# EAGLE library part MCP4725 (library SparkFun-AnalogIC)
Microchip 12-bit I2C DAC, SOT23-6

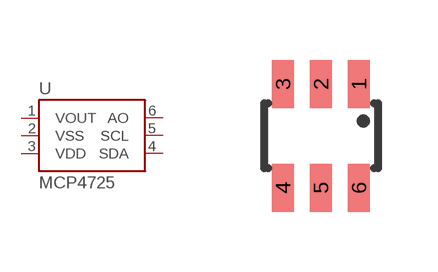
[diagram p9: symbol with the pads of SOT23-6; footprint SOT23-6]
Designator prefix U

## MCP4725SOT-23 (PROD_ID: IC-08886; VALUE: MCP4725)  [SOT23-6]
1  VOUT
2  VSS
3  VDD
4  SDA
5  SCL
6  AO

## Footprint SOT23-6 (pad centres in mm)
smd 0.55 x 1.2: 1 0.95,1.3; 2 0,1.3; 3 -0.95,1.3; 4 -0.95,-1.3; 5 0,-1.3; 6 0.95,-1.3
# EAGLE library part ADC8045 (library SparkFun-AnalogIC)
Unity-gain stable feedback amplifier. Low noise, low distortion, 1GHz BW.

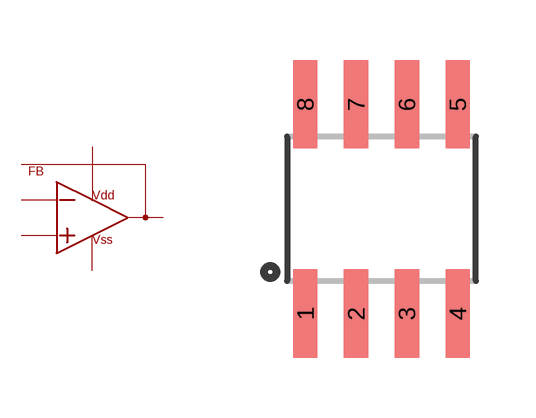
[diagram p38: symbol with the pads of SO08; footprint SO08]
Designator prefix U

## ADC8045 (PROD_ID: IC-11224; VALUE: ADC8045)  [SO08]
1  FB
2  IN-
3  IN+
4  VSS
6  OUT
7  VDD

## Footprint SO08 (pad centres in mm)
Small Outline Package Fits JEDEC packages (narrow SOIC-8)
smd 0.61 x 2.21: 1 -1.905,-2.616; 2 -0.635,-2.616; 3 0.635,-2.616; 4 1.905,-2.616; 5 1.905,2.616; 6 0.635,2.616; 7 -0.635,2.616; 8 -1.905,2.616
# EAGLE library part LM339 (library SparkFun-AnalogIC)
Based on information from the SLCS006N datasheet from TI (www.ti.com). Change Log DateAuthorChange July 16, 2008nick@scantool.netDevice created.

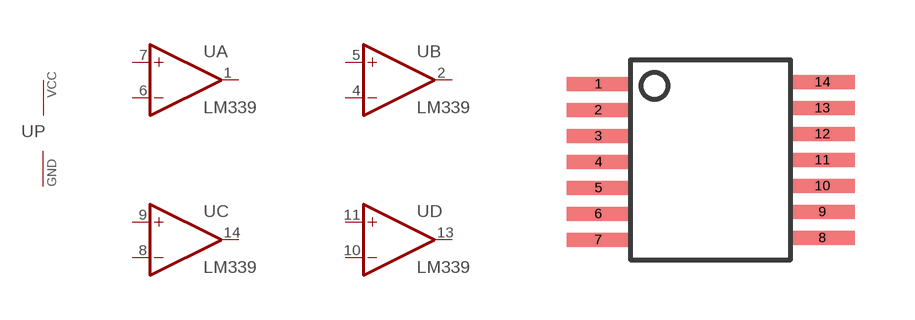
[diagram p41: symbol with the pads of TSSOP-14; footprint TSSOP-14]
Designator prefix U; gates B=LM339 A=LM339 C=LM339 D=LM339 P=PWRN

## LM339 (DESC: IC, Quad Comparator; MANUF: Texas Instruments; PARTNUM: LM339PWR; SUPPLIER: Digikey:296-6607-1-ND; VALSTAT: PARTNUM)  [TSSOP-14]
1  A:OUT  out
2  B:OUT  out
3  P:VCC  pwr
4  B:-IN  in
5  B:+IN  in
6  A:-IN  in
7  A:+IN  in
8  C:-IN  in
9  C:+IN  in
10  D:-IN  in
11  D:+IN  in
12  P:GND  pwr
13  D:OUT  out
14  C:OUT  out

## Footprint TSSOP-14 (pad centres in mm)
smd 1.6 x 0.35: 1 -2.8,1.9; 2 -2.8,1.25; 3 -2.8,0.6; 4 -2.8,-0.05; 5 -2.8,-0.7; 6 -2.8,-1.35; 7 -2.8,-2; 8 2.8,-1.95; 9 2.8,-1.3; 10 2.8,-0.65; 11 2.8,0; 12 2.8,0.65; 13 2.8,1.3; 14 2.8,1.95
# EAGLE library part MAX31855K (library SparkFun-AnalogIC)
Cold-Junction-Compensated K-Thermocoupleto-Digital Converter (-270°C to +1800°C) The MAX31855K performs cold-junction compensation and digitizes the signal from a type-K thermocouple. The data is output in a 14-bit resolution, SPI™-compatible, read-only format. This converter resolves temperatures to 0.25°C, allows readings as high as +1800°C and as low as -270°C, and exhibits thermocouple accuracy of ±2°C for temperatures ranging from -200°C to +700°C for K-type thermocouples.

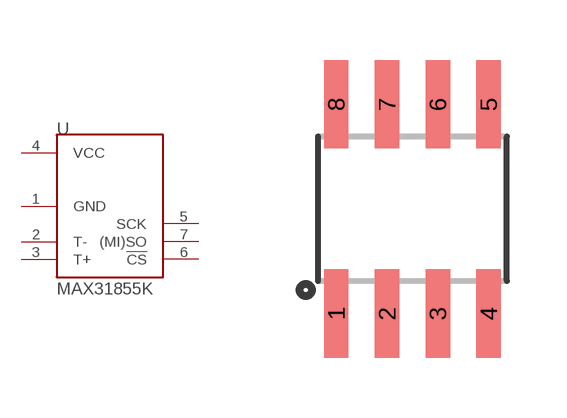
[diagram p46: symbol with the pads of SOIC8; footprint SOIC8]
Designator prefix U

## MAX31855K  [SOIC8]
1  GND
2  T-
3  T+
4  VCC
5  SCK
6  !CS
7  (MI)SO

## Footprint SOIC8 (pad centres in mm)
smd 0.61 x 2.21: 1 -1.905,-2.616; 2 -0.635,-2.616; 3 0.635,-2.616; 4 1.905,-2.616; 5 1.905,2.616; 6 0.635,2.616; 7 -0.635,2.616; 8 -1.905,2.616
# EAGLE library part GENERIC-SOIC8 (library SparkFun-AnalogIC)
A placeholder for generic narrow & wide SOIC8 foorptints - used on the DIP adapter board.

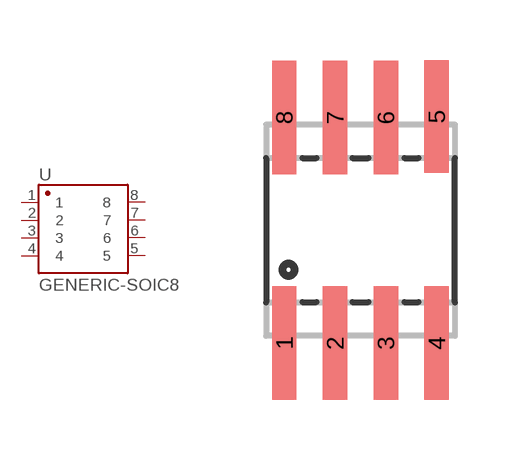
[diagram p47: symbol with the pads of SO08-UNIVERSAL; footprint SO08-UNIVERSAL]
Designator prefix U

## GENERIC-SOIC8  [SO08-UNIVERSAL]
1  1
2  2
3  3
4  4
5  5
6  6
7  7
8  8

## Footprint SO08-UNIVERSAL (pad centres in mm)
SOIC-08 footprint wth long lands. To fit both narrow and wide SOICs - for SOIC-to-DIP adapter board. Not recommended if you're trying to fit a specific chip.
smd 0.61 x 2.845: 1 -1.905,-2.819; 2 -0.635,-2.819; 3 0.635,-2.819; 4 1.905,-2.819; 6 0.635,2.819; 7 -0.635,2.819; 8 -1.905,2.819
smd 0.61 x 2.819: 5 1.905,2.845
